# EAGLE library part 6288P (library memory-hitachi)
MEMORY

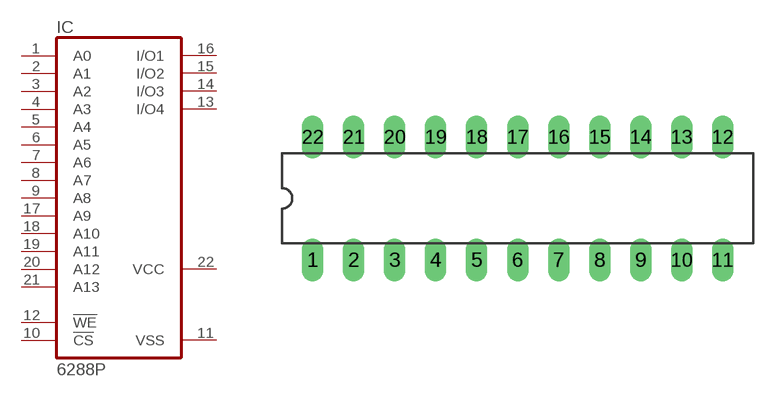
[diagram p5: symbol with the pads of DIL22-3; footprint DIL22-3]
Designator prefix IC

## 6288P (OC_FARNELL: unknown; OC_NEWARK: unknown)  [DIL22-3]
1  A0  in
2  A1  in
3  A2  in
4  A3  in
5  A4  in
6  A5  in
7  A6  in
8  A7  in
9  A8  in
10  !CS  in
11  VSS  pwr
12  !WE  in
13  I/O4
14  I/O3
15  I/O2
16  I/O1
17  A9  in
18  A10  in
19  A11  in
20  A12  in
21  A13  in
22  VCC  pwr

## Footprint DIL22-3 (pad centres in mm)
Dual In Line Package 0.3 inch
drill 0.813 long: 1 -12.7,-3.81; 2 -10.16,-3.81; 3 -7.62,-3.81; 4 -5.08,-3.81; 5 -2.54,-3.81; 6 0,-3.81; 7 2.54,-3.81; 8 5.08,-3.81; 9 7.62,-3.81; 10 10.16,-3.81; 11 12.7,-3.81; 12 12.7,3.81; 13 10.16,3.81; 14 7.62,3.81; 15 5.08,3.81; 16 2.54,3.81; 17 0,3.81; 18 -2.54,3.81; 19 -5.08,3.81; 20 -7.62,3.81; 21 -10.16,3.81; 22 -12.7,3.81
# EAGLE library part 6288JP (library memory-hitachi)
MEMORY

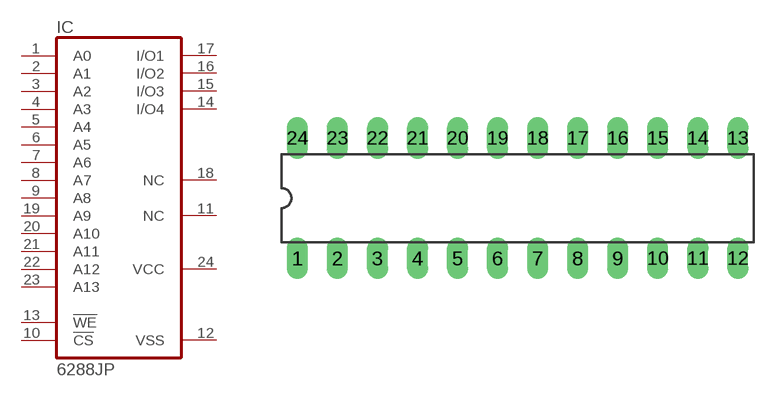
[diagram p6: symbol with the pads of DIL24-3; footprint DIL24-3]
Designator prefix IC

## 6288JP (OC_FARNELL: unknown; OC_NEWARK: unknown)  [DIL24-3]
1  A0  in
2  A1  in
3  A2  in
4  A3  in
5  A4  in
6  A5  in
7  A6  in
8  A7  in
9  A8  in
10  !CS  in
11  NC  nc
12  VSS  pwr
13  !WE  in
14  I/O4
15  I/O3
16  I/O2
17  I/O1
18  NC  nc
19  A9  in
20  A10  in
21  A11  in
22  A12  in
23  A13  in
24  VCC  pwr

## Footprint DIL24-3 (pad centres in mm)
Dual In Line Package 0.3 inch
drill 0.813 long: 1 -13.97,-3.81; 2 -11.43,-3.81; 3 -8.89,-3.81; 4 -6.35,-3.81; 5 -3.81,-3.81; 6 -1.27,-3.81; 7 1.27,-3.81; 8 3.81,-3.81; 9 6.35,-3.81; 10 8.89,-3.81; 11 11.43,-3.81; 12 13.97,-3.81; 13 13.97,3.81; 14 11.43,3.81; 15 8.89,3.81; 16 6.35,3.81; 17 3.81,3.81; 18 1.27,3.81; 19 -1.27,3.81; 20 -3.81,3.81; 21 -6.35,3.81; 22 -8.89,3.81; 23 -11.43,3.81; 24 -13.97,3.81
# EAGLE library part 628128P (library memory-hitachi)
MEMORY

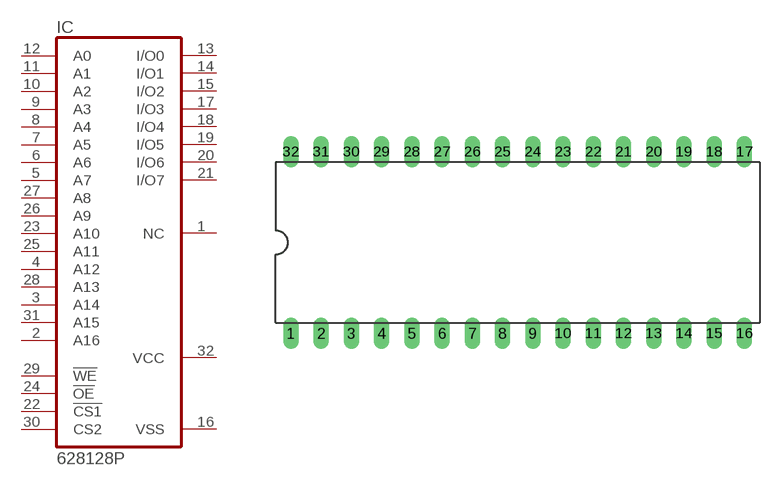
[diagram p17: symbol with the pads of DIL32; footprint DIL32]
Designator prefix IC

## 628128P (OC_FARNELL: unknown; OC_NEWARK: unknown)  [DIL32]
1  NC  nc
2  A16  in
3  A14  in
4  A12  in
5  A7  in
6  A6  in
7  A5  in
8  A4  in
9  A3  in
10  A2  in
11  A1  in
12  A0  in
13  I/O0
14  I/O1
15  I/O2
16  VSS  pwr
17  I/O3
18  I/O4
19  I/O5
20  I/O6
21  I/O7
22  !CS1  in
23  A10  in
24  !OE  in
25  A11  in
26  A9  in
27  A8  in
28  A13  in
29  !WE  in
30  CS2  in
31  A15  in
32  VCC  pwr

## Footprint DIL32 (pad centres in mm)
Dual In Line Package
drill 0.813 long: 1 -19.05,-7.62; 2 -16.51,-7.62; 3 -13.97,-7.62; 4 -11.43,-7.62; 5 -8.89,-7.62; 6 -6.35,-7.62; 7 -3.81,-7.62; 8 -1.27,-7.62; 9 1.27,-7.62; 10 3.81,-7.62; 11 6.35,-7.62; 12 8.89,-7.62; 13 11.43,-7.62; 14 13.97,-7.62; 15 16.51,-7.62; 16 19.05,-7.62; 17 19.05,7.62; 18 16.51,7.62; 19 13.97,7.62; 20 11.43,7.62; 21 8.89,7.62; 22 6.35,7.62; 23 3.81,7.62; 24 1.27,7.62; 25 -1.27,7.62; 26 -3.81,7.62; 27 -6.35,7.62; 28 -8.89,7.62; 29 -11.43,7.62; 30 -13.97,7.62; 31 -16.51,7.62; 32 -19.05,7.62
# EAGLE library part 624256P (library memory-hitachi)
MEMORY

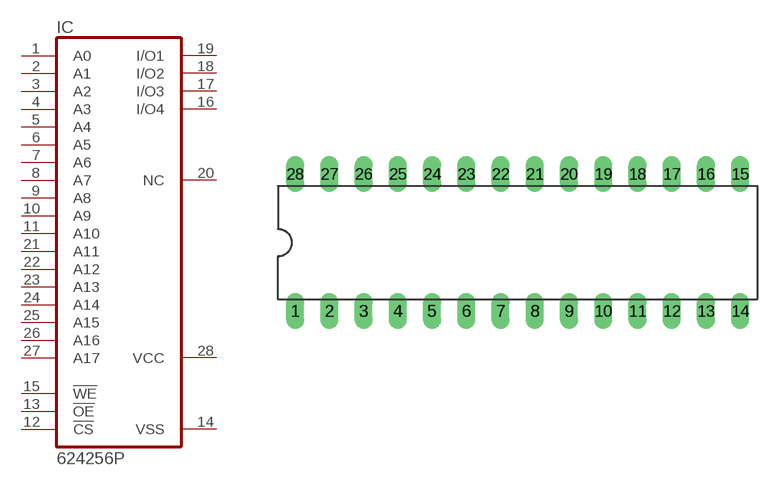
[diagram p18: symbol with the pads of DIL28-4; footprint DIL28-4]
Designator prefix IC

## 624256P (OC_FARNELL: unknown; OC_NEWARK: unknown)  [DIL28-4]
1  A0  in
2  A1  in
3  A2  in
4  A3  in
5  A4  in
6  A5  in
7  A6  in
8  A7  in
9  A8  in
10  A9  in
11  A10  in
12  !CS  in
13  !OE  in
14  VSS  pwr
15  !WE  in
16  I/O4
17  I/O3
18  I/O2
19  I/O1
20  NC  nc
21  A11  in
22  A12  in
23  A13  in
24  A14  in
25  A15  in
26  A16  in
27  A17  in
28  VCC  pwr

## Footprint DIL28-4 (pad centres in mm)
Dual In Line Package
drill 0.813 long: 1 -16.51,-5.08; 2 -13.97,-5.08; 3 -11.43,-5.08; 4 -8.89,-5.08; 5 -6.35,-5.08; 6 -3.81,-5.08; 7 -1.27,-5.08; 8 1.27,-5.08; 9 3.81,-5.08; 10 6.35,-5.08; 11 8.89,-5.08; 12 11.43,-5.08; 13 13.97,-5.08; 14 16.51,-5.08; 15 16.51,5.08; 16 13.97,5.08; 17 11.43,5.08; 18 8.89,5.08; 19 6.35,5.08; 20 3.81,5.08; 21 1.27,5.08; 22 -1.27,5.08; 23 -3.81,5.08; 24 -6.35,5.08; 25 -8.89,5.08; 26 -11.43,5.08; 27 -13.97,5.08; 28 -16.51,5.08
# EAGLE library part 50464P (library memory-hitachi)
MEMORY

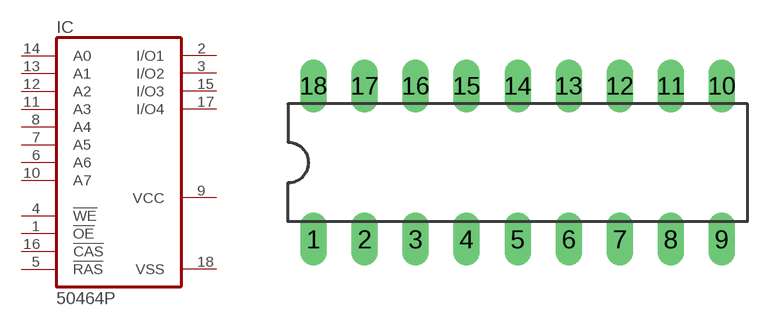
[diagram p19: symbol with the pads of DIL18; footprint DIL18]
Designator prefix IC

## 50464P (OC_FARNELL: unknown; OC_NEWARK: unknown)  [DIL18]
1  !OE  in
2  I/O1
3  I/O2
4  !WE  in
5  !RAS  in
6  A6  in
7  A5  in
8  A4  in
9  VCC  pwr
10  A7  in
11  A3  in
12  A2  in
13  A1  in
14  A0  in
15  I/O3
16  !CAS  in
17  I/O4
18  VSS  pwr

## Footprint DIL18 (pad centres in mm)
Dual In Line Package
drill 0.813 long: 1 -10.16,-3.81; 2 -7.62,-3.81; 3 -5.08,-3.81; 4 -2.54,-3.81; 5 0,-3.81; 6 2.54,-3.81; 7 5.08,-3.81; 8 7.62,-3.81; 9 10.16,-3.81; 10 10.16,3.81; 11 7.62,3.81; 12 5.08,3.81; 13 2.54,3.81; 14 0,3.81; 15 -2.54,3.81; 16 -5.08,3.81; 17 -7.62,3.81; 18 -10.16,3.81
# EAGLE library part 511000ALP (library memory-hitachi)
MEMORY

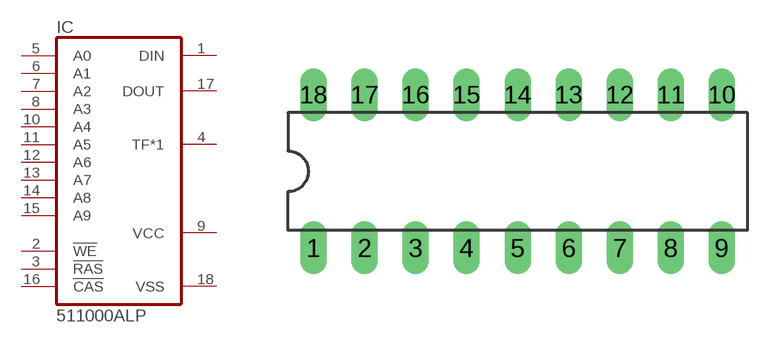
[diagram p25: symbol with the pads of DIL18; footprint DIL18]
Designator prefix IC

## 511000ALP (OC_FARNELL: unknown; OC_NEWARK: unknown)  [DIL18]
1  DIN  in
2  !WE  in
3  !RAS  in
4  TF*1  pas
5  A0  in
6  A1  in
7  A2  in
8  A3  in
9  VCC  pwr
10  A4  in
11  A5  in
12  A6  in
13  A7  in
14  A8  in
15  A9  in
16  !CAS  in
17  DOUT  hiz
18  VSS  pwr

## Footprint DIL18 (pad centres in mm)
Dual In Line Package
drill 0.813 long: 1 -10.16,-3.81; 2 -7.62,-3.81; 3 -5.08,-3.81; 4 -2.54,-3.81; 5 0,-3.81; 6 2.54,-3.81; 7 5.08,-3.81; 8 7.62,-3.81; 9 10.16,-3.81; 10 10.16,3.81; 11 7.62,3.81; 12 5.08,3.81; 13 2.54,3.81; 14 0,3.81; 15 -2.54,3.81; 16 -5.08,3.81; 17 -7.62,3.81; 18 -10.16,3.81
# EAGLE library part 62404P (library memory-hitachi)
MEMORY

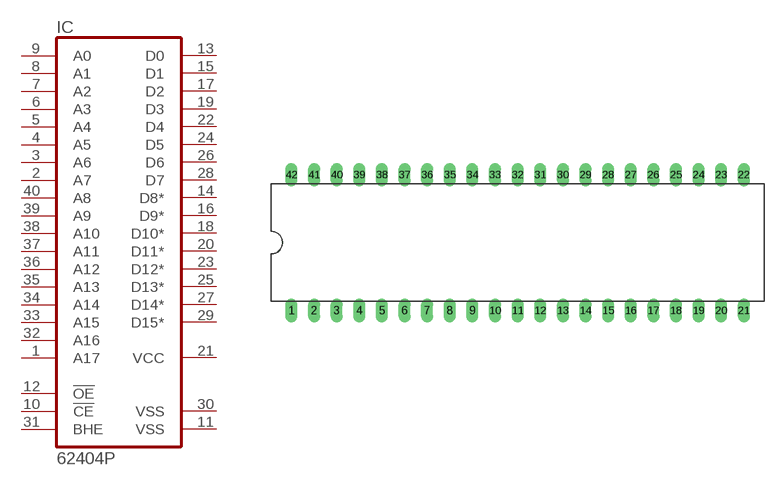
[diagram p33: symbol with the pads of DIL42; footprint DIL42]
Designator prefix IC

## 62404P (OC_FARNELL: unknown; OC_NEWARK: unknown)  [DIL42]
1  A17  in
2  A7  in
3  A6  in
4  A5  in
5  A4  in
6  A3  in
7  A2  in
8  A1  in
9  A0  in
10  !CE  in
11  VSS  pwr
12  !OE  in
13  D0  hiz
14  D8*  hiz
15  D1  hiz
16  D9*  hiz
17  D2  hiz
18  D10*  hiz
19  D3  hiz
20  D11*  hiz
21  VCC  pwr
22  D4  hiz
23  D12*  hiz
24  D5  hiz
25  D13*  hiz
26  D6  hiz
27  D14*  hiz
28  D7  hiz
29  D15*  hiz
30  VSS  pwr
31  BHE  in
32  A16  in
33  A15  in
34  A14  in
35  A13  in
36  A12  in
37  A11  in
38  A10  in
39  A9  in
40  A8  in

## Footprint DIL42 (pad centres in mm)
Dual In Line Package
drill 0.813 long: 1 -25.4,-7.62; 2 -22.86,-7.62; 3 -20.32,-7.62; 4 -17.78,-7.62; 5 -15.24,-7.62; 6 -12.7,-7.62; 7 -10.16,-7.62; 8 -7.62,-7.62; 9 -5.08,-7.62; 10 -2.54,-7.62; 11 0,-7.62; 12 2.54,-7.62; 13 5.08,-7.62; 14 7.62,-7.62; 15 10.16,-7.62; 16 12.7,-7.62; 17 15.24,-7.62; 18 17.78,-7.62; 19 20.32,-7.62; 20 22.86,-7.62; 21 25.4,-7.62; 22 25.4,7.62; 23 22.86,7.62; 24 20.32,7.62; 25 17.78,7.62; 26 15.24,7.62; 27 12.7,7.62; 28 10.16,7.62; 29 7.62,7.62; 30 5.08,7.62; 31 2.54,7.62; 32 0,7.62; 33 -2.54,7.62; 34 -5.08,7.62; 35 -7.62,7.62; 36 -10.16,7.62; 37 -12.7,7.62; 38 -15.24,7.62; 39 -17.78,7.62; 40 -20.32,7.62; 41 -22.86,7.62; 42 -25.4,7.62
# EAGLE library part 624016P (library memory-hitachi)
MEMORY

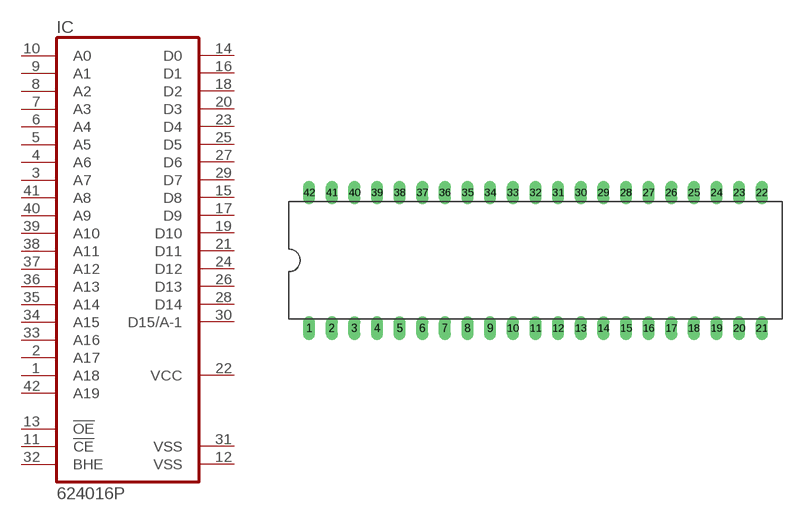
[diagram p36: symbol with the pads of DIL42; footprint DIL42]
Designator prefix IC

## 624016P (OC_FARNELL: unknown; OC_NEWARK: unknown)  [DIL42]
1  A18  in
2  A17  in
3  A7  in
4  A6  in
5  A5  in
6  A4  in
7  A3  in
8  A2  in
9  A1  in
10  A0  in
11  !CE  in
12  VSS  pwr
13  !OE  in
14  D0  hiz
15  D8  hiz
16  D1  hiz
17  D9  hiz
18  D2  hiz
19  D10  hiz
20  D3  hiz
21  D11  hiz
22  VCC  pwr
23  D4  hiz
24  D12  hiz
25  D5  hiz
26  D13  hiz
27  D6  hiz
28  D14  hiz
29  D7  hiz
30  D15/A-1  hiz
31  VSS  pwr
32  BHE  in
33  A16  in
34  A15  in
35  A14  in
36  A13  in
37  A12  in
38  A11  in
39  A10  in
40  A9  in
41  A8  in
42  A19  in

## Footprint DIL42 (pad centres in mm)
Dual In Line Package
drill 0.813 long: 1 -25.4,-7.62; 2 -22.86,-7.62; 3 -20.32,-7.62; 4 -17.78,-7.62; 5 -15.24,-7.62; 6 -12.7,-7.62; 7 -10.16,-7.62; 8 -7.62,-7.62; 9 -5.08,-7.62; 10 -2.54,-7.62; 11 0,-7.62; 12 2.54,-7.62; 13 5.08,-7.62; 14 7.62,-7.62; 15 10.16,-7.62; 16 12.7,-7.62; 17 15.24,-7.62; 18 17.78,-7.62; 19 20.32,-7.62; 20 22.86,-7.62; 21 25.4,-7.62; 22 25.4,7.62; 23 22.86,7.62; 24 20.32,7.62; 25 17.78,7.62; 26 15.24,7.62; 27 12.7,7.62; 28 10.16,7.62; 29 7.62,7.62; 30 5.08,7.62; 31 2.54,7.62; 32 0,7.62; 33 -2.54,7.62; 34 -5.08,7.62; 35 -7.62,7.62; 36 -10.16,7.62; 37 -12.7,7.62; 38 -15.24,7.62; 39 -17.78,7.62; 40 -20.32,7.62; 41 -22.86,7.62; 42 -25.4,7.62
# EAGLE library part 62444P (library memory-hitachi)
MEMORY

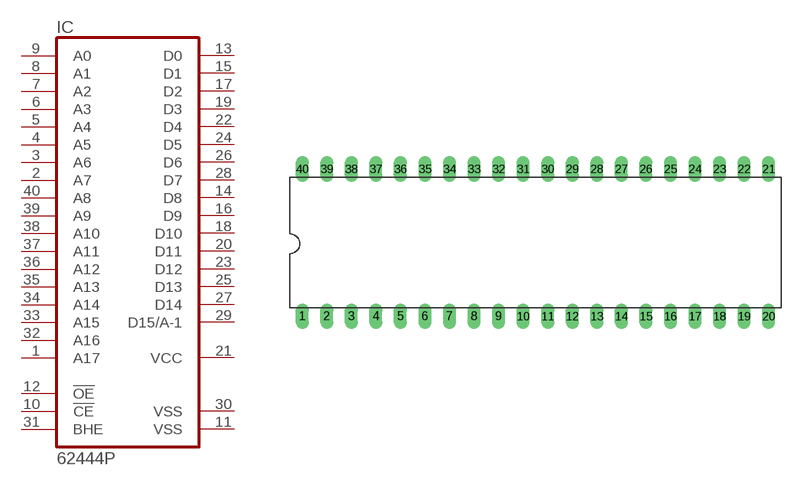
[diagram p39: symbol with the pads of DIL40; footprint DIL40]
Designator prefix IC

## 62444P (OC_FARNELL: unknown; OC_NEWARK: unknown)  [DIL40]
1  A17  in
2  A7  in
3  A6  in
4  A5  in
5  A4  in
6  A3  in
7  A2  in
8  A1  in
9  A0  in
10  !CE  in
11  VSS  pwr
12  !OE  in
13  D0  hiz
14  D8  hiz
15  D1  hiz
16  D9  hiz
17  D2  hiz
18  D10  hiz
19  D3  hiz
20  D11  hiz
21  VCC  pwr
22  D4  hiz
23  D12  hiz
24  D5  hiz
25  D13  hiz
26  D6  hiz
27  D14  hiz
28  D7  hiz
29  D15/A-1  hiz
30  VSS  pwr
31  BHE  in
32  A16  in
33  A15  in
34  A14  in
35  A13  in
36  A12  in
37  A11  in
38  A10  in
39  A9  in
40  A8  in

## Footprint DIL40 (pad centres in mm)
Dual In Line Package
drill 0.813 long: 1 -24.13,-7.62; 2 -21.59,-7.62; 3 -19.05,-7.62; 4 -16.51,-7.62; 5 -13.97,-7.62; 6 -11.43,-7.62; 7 -8.89,-7.62; 8 -6.35,-7.62; 9 -3.81,-7.62; 10 -1.27,-7.62; 11 1.27,-7.62; 12 3.81,-7.62; 13 6.35,-7.62; 14 8.89,-7.62; 15 11.43,-7.62; 16 13.97,-7.62; 17 16.51,-7.62; 18 19.05,-7.62; 19 21.59,-7.62; 20 24.13,-7.62; 21 24.13,7.62; 22 21.59,7.62; 23 19.05,7.62; 24 16.51,7.62; 25 13.97,7.62; 26 11.43,7.62; 27 8.89,7.62; 28 6.35,7.62; 29 3.81,7.62; 30 1.27,7.62; 31 -1.27,7.62; 32 -3.81,7.62; 33 -6.35,7.62; 34 -8.89,7.62; 35 -11.43,7.62; 36 -13.97,7.62; 37 -16.51,7.62; 38 -19.05,7.62; 39 -21.59,7.62; 40 -24.13,7.62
